VERSION 5.7 ;
  NOWIREEXTENSIONATPIN ON ;
  DIVIDERCHAR "/" ;
  BUSBITCHARS "[]" ;
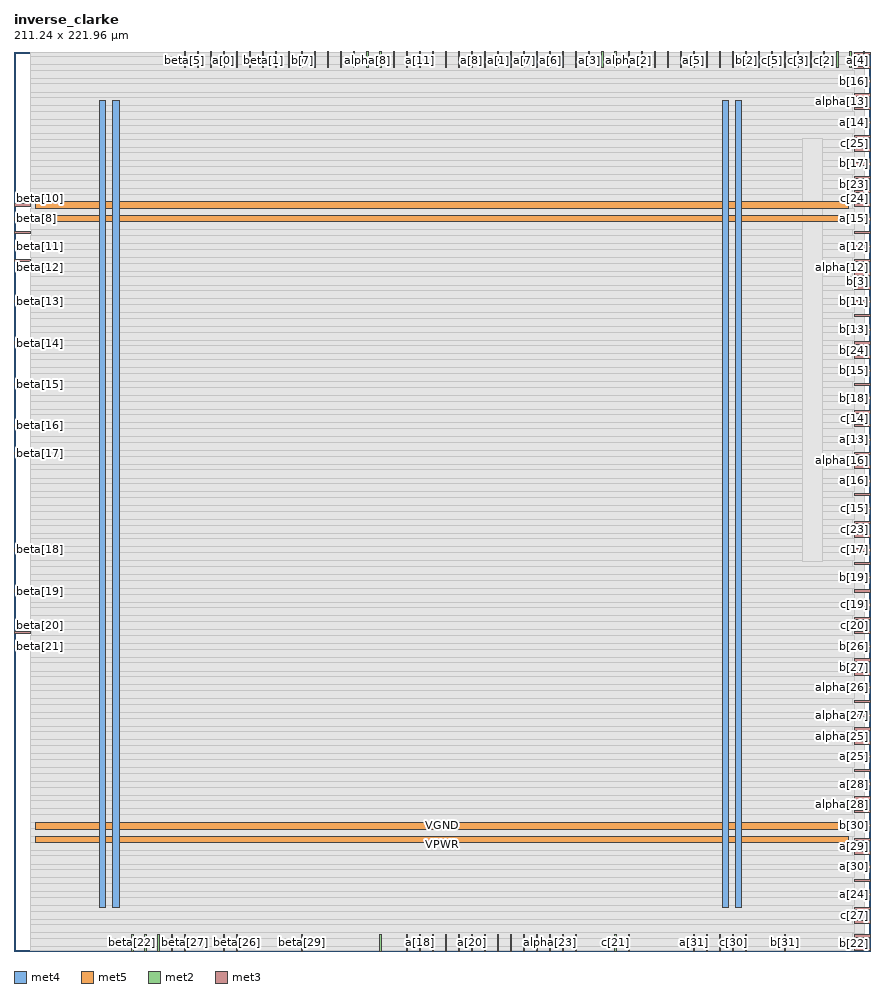
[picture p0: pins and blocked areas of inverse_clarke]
MACRO inverse_clarke
  CLASS BLOCK ;
  FOREIGN inverse_clarke ;
  ORIGIN 0.000 0.000 ;
  SIZE 211.240 BY 221.960 ;
  PIN VGND
    DIRECTION INOUT ;
    USE GROUND ;
    PORT
      LAYER met4 ;
        RECT 24.340 10.640 25.940 209.680 ;
    END
    PORT
      LAYER met4 ;
        RECT 177.940 10.640 179.540 209.680 ;
    END
    PORT
      LAYER met5 ;
        RECT 5.280 30.030 205.860 31.630 ;
    END
    PORT
      LAYER met5 ;
        RECT 5.280 183.210 205.860 184.810 ;
    END
  END VGND
  PIN VPWR
    DIRECTION INOUT ;
    USE POWER ;
    PORT
      LAYER met4 ;
        RECT 21.040 10.640 22.640 209.680 ;
    END
    PORT
      LAYER met4 ;
        RECT 174.640 10.640 176.240 209.680 ;
    END
    PORT
      LAYER met5 ;
        RECT 5.280 26.730 205.860 28.330 ;
    END
    PORT
      LAYER met5 ;
        RECT 5.280 179.910 205.860 181.510 ;
    END
  END VPWR
  PIN a[0]
    DIRECTION OUTPUT ;
    USE SIGNAL ;
    ANTENNADIFFAREA 0.795200 ;
    PORT
      LAYER met2 ;
        RECT 51.610 217.960 51.890 221.960 ;
    END
  END a[0]
  PIN a[10]
    DIRECTION OUTPUT ;
    USE SIGNAL ;
    ANTENNADIFFAREA 0.795200 ;
    PORT
      LAYER met2 ;
        RECT 58.050 217.960 58.330 221.960 ;
    END
  END a[10]
  PIN a[11]
    DIRECTION OUTPUT ;
    USE SIGNAL ;
    ANTENNADIFFAREA 0.795200 ;
    PORT
      LAYER met2 ;
        RECT 99.910 217.960 100.190 221.960 ;
    END
  END a[11]
  PIN a[12]
    DIRECTION OUTPUT ;
    USE SIGNAL ;
    ANTENNADIFFAREA 0.445500 ;
    PORT
      LAYER met3 ;
        RECT 207.240 173.440 211.240 174.040 ;
    END
  END a[12]
  PIN a[13]
    DIRECTION OUTPUT ;
    USE SIGNAL ;
    ANTENNADIFFAREA 0.795200 ;
    PORT
      LAYER met3 ;
        RECT 207.240 125.840 211.240 126.440 ;
    END
  END a[13]
  PIN a[14]
    DIRECTION OUTPUT ;
    USE SIGNAL ;
    ANTENNADIFFAREA 0.795200 ;
    PORT
      LAYER met3 ;
        RECT 207.240 204.040 211.240 204.640 ;
    END
  END a[14]
  PIN a[15]
    DIRECTION OUTPUT ;
    USE SIGNAL ;
    ANTENNADIFFAREA 0.795200 ;
    PORT
      LAYER met3 ;
        RECT 207.240 180.240 211.240 180.840 ;
    END
  END a[15]
  PIN a[16]
    DIRECTION OUTPUT ;
    USE SIGNAL ;
    ANTENNADIFFAREA 0.795200 ;
    PORT
      LAYER met3 ;
        RECT 207.240 115.640 211.240 116.240 ;
    END
  END a[16]
  PIN a[17]
    DIRECTION OUTPUT ;
    USE SIGNAL ;
    ANTENNADIFFAREA 0.795200 ;
    PORT
      LAYER met3 ;
        RECT 207.240 112.240 211.240 112.840 ;
    END
  END a[17]
  PIN a[18]
    DIRECTION OUTPUT ;
    USE SIGNAL ;
    ANTENNADIFFAREA 0.795200 ;
    PORT
      LAYER met2 ;
        RECT 99.910 0.000 100.190 4.000 ;
    END
  END a[18]
  PIN a[19]
    DIRECTION OUTPUT ;
    USE SIGNAL ;
    ANTENNADIFFAREA 0.795200 ;
    PORT
      LAYER met2 ;
        RECT 103.130 0.000 103.410 4.000 ;
    END
  END a[19]
  PIN a[1]
    DIRECTION OUTPUT ;
    USE SIGNAL ;
    ANTENNADIFFAREA 0.795200 ;
    PORT
      LAYER met2 ;
        RECT 119.230 217.960 119.510 221.960 ;
    END
  END a[1]
  PIN a[20]
    DIRECTION OUTPUT ;
    USE SIGNAL ;
    ANTENNADIFFAREA 0.795200 ;
    PORT
      LAYER met2 ;
        RECT 112.790 0.000 113.070 4.000 ;
    END
  END a[20]
  PIN a[21]
    DIRECTION OUTPUT ;
    USE SIGNAL ;
    ANTENNADIFFAREA 0.795200 ;
    PORT
      LAYER met2 ;
        RECT 122.450 0.000 122.730 4.000 ;
    END
  END a[21]
  PIN a[22]
    DIRECTION OUTPUT ;
    USE SIGNAL ;
    ANTENNADIFFAREA 0.795200 ;
    PORT
      LAYER met2 ;
        RECT 125.670 0.000 125.950 4.000 ;
    END
  END a[22]
  PIN a[23]
    DIRECTION OUTPUT ;
    USE SIGNAL ;
    ANTENNADIFFAREA 0.795200 ;
    PORT
      LAYER met2 ;
        RECT 135.330 0.000 135.610 4.000 ;
    END
  END a[23]
  PIN a[24]
    DIRECTION OUTPUT ;
    USE SIGNAL ;
    ANTENNADIFFAREA 0.795200 ;
    PORT
      LAYER met3 ;
        RECT 207.240 13.640 211.240 14.240 ;
    END
  END a[24]
  PIN a[25]
    DIRECTION OUTPUT ;
    USE SIGNAL ;
    ANTENNADIFFAREA 0.445500 ;
    PORT
      LAYER met3 ;
        RECT 207.240 47.640 211.240 48.240 ;
    END
  END a[25]
  PIN a[26]
    DIRECTION OUTPUT ;
    USE SIGNAL ;
    ANTENNADIFFAREA 0.795200 ;
    PORT
      LAYER met3 ;
        RECT 207.240 71.440 211.240 72.040 ;
    END
  END a[26]
  PIN a[27]
    DIRECTION OUTPUT ;
    USE SIGNAL ;
    ANTENNADIFFAREA 0.795200 ;
    PORT
      LAYER met3 ;
        RECT 207.240 6.840 211.240 7.440 ;
    END
  END a[27]
  PIN a[28]
    DIRECTION OUTPUT ;
    USE SIGNAL ;
    ANTENNADIFFAREA 0.795200 ;
    PORT
      LAYER met3 ;
        RECT 207.240 40.840 211.240 41.440 ;
    END
  END a[28]
  PIN a[29]
    DIRECTION OUTPUT ;
    USE SIGNAL ;
    ANTENNADIFFAREA 0.795200 ;
    PORT
      LAYER met3 ;
        RECT 207.240 27.240 211.240 27.840 ;
    END
  END a[29]
  PIN a[2]
    DIRECTION OUTPUT ;
    USE SIGNAL ;
    ANTENNADIFFAREA 0.795200 ;
    PORT
      LAYER met2 ;
        RECT 135.330 217.960 135.610 221.960 ;
    END
  END a[2]
  PIN a[30]
    DIRECTION OUTPUT ;
    USE SIGNAL ;
    ANTENNADIFFAREA 0.795200 ;
    PORT
      LAYER met3 ;
        RECT 207.240 20.440 211.240 21.040 ;
    END
  END a[30]
  PIN a[31]
    DIRECTION OUTPUT ;
    USE SIGNAL ;
    ANTENNADIFFAREA 0.795200 ;
    PORT
      LAYER met2 ;
        RECT 167.530 0.000 167.810 4.000 ;
    END
  END a[31]
  PIN a[3]
    DIRECTION OUTPUT ;
    USE SIGNAL ;
    ANTENNADIFFAREA 0.795200 ;
    PORT
      LAYER met2 ;
        RECT 141.770 217.960 142.050 221.960 ;
    END
  END a[3]
  PIN a[4]
    DIRECTION OUTPUT ;
    USE SIGNAL ;
    ANTENNADIFFAREA 0.795200 ;
    PORT
      LAYER met2 ;
        RECT 209.390 217.960 209.670 221.960 ;
    END
  END a[4]
  PIN a[5]
    DIRECTION OUTPUT ;
    USE SIGNAL ;
    ANTENNADIFFAREA 0.795200 ;
    PORT
      LAYER met2 ;
        RECT 167.530 217.960 167.810 221.960 ;
    END
  END a[5]
  PIN a[6]
    DIRECTION OUTPUT ;
    USE SIGNAL ;
    ANTENNADIFFAREA 0.795200 ;
    PORT
      LAYER met2 ;
        RECT 132.110 217.960 132.390 221.960 ;
    END
  END a[6]
  PIN a[7]
    DIRECTION OUTPUT ;
    USE SIGNAL ;
    ANTENNADIFFAREA 0.795200 ;
    PORT
      LAYER met2 ;
        RECT 125.670 217.960 125.950 221.960 ;
    END
  END a[7]
  PIN a[8]
    DIRECTION OUTPUT ;
    USE SIGNAL ;
    ANTENNADIFFAREA 0.795200 ;
    PORT
      LAYER met2 ;
        RECT 112.790 217.960 113.070 221.960 ;
    END
  END a[8]
  PIN a[9]
    DIRECTION OUTPUT ;
    USE SIGNAL ;
    ANTENNADIFFAREA 0.795200 ;
    PORT
      LAYER met2 ;
        RECT 103.130 217.960 103.410 221.960 ;
    END
  END a[9]
  PIN alpha[0]
    DIRECTION INPUT ;
    USE SIGNAL ;
    ANTENNAGATEAREA 0.495000 ;
    PORT
      LAYER met2 ;
        RECT 144.990 217.960 145.270 221.960 ;
    END
  END alpha[0]
  PIN alpha[10]
    DIRECTION INPUT ;
    USE SIGNAL ;
    ANTENNAGATEAREA 0.213000 ;
    PORT
      LAYER met2 ;
        RECT 96.690 217.960 96.970 221.960 ;
    END
  END alpha[10]
  PIN alpha[11]
    DIRECTION INPUT ;
    USE SIGNAL ;
    ANTENNAGATEAREA 0.196500 ;
    PORT
      LAYER met2 ;
        RECT 106.350 217.960 106.630 221.960 ;
    END
  END alpha[11]
  PIN alpha[12]
    DIRECTION INPUT ;
    USE SIGNAL ;
    ANTENNAGATEAREA 0.196500 ;
    PORT
      LAYER met3 ;
        RECT 207.240 170.040 211.240 170.640 ;
    END
  END alpha[12]
  PIN alpha[13]
    DIRECTION INPUT ;
    USE SIGNAL ;
    ANTENNAGATEAREA 0.213000 ;
    PORT
      LAYER met3 ;
        RECT 207.240 207.440 211.240 208.040 ;
    END
  END alpha[13]
  PIN alpha[14]
    DIRECTION INPUT ;
    USE SIGNAL ;
    ANTENNAGATEAREA 0.196500 ;
    PORT
      LAYER met3 ;
        RECT 207.240 132.640 211.240 133.240 ;
    END
  END alpha[14]
  PIN alpha[15]
    DIRECTION INPUT ;
    USE SIGNAL ;
    ANTENNAGATEAREA 0.196500 ;
    PORT
      LAYER met3 ;
        RECT 207.240 200.640 211.240 201.240 ;
    END
  END alpha[15]
  PIN alpha[16]
    DIRECTION INPUT ;
    USE SIGNAL ;
    ANTENNAGATEAREA 0.126000 ;
    PORT
      LAYER met3 ;
        RECT 207.240 119.040 211.240 119.640 ;
    END
  END alpha[16]
  PIN alpha[17]
    DIRECTION INPUT ;
    USE SIGNAL ;
    ANTENNAGATEAREA 0.196500 ;
    PORT
      LAYER met3 ;
        RECT 207.240 122.440 211.240 123.040 ;
    END
  END alpha[17]
  PIN alpha[18]
    DIRECTION INPUT ;
    USE SIGNAL ;
    ANTENNAGATEAREA 0.126000 ;
    PORT
      LAYER met2 ;
        RECT 106.350 0.000 106.630 4.000 ;
    END
  END alpha[18]
  PIN alpha[19]
    DIRECTION INPUT ;
    USE SIGNAL ;
    ANTENNAGATEAREA 0.159000 ;
    PORT
      LAYER met2 ;
        RECT 109.570 0.000 109.850 4.000 ;
    END
  END alpha[19]
  PIN alpha[1]
    DIRECTION INPUT ;
    USE SIGNAL ;
    ANTENNAGATEAREA 0.742500 ;
    PORT
      LAYER met2 ;
        RECT 138.550 217.960 138.830 221.960 ;
    END
  END alpha[1]
  PIN alpha[20]
    DIRECTION INPUT ;
    USE SIGNAL ;
    ANTENNAGATEAREA 0.196500 ;
    PORT
      LAYER met2 ;
        RECT 116.010 0.000 116.290 4.000 ;
    END
  END alpha[20]
  PIN alpha[21]
    DIRECTION INPUT ;
    USE SIGNAL ;
    ANTENNAGATEAREA 0.196500 ;
    PORT
      LAYER met2 ;
        RECT 119.230 0.000 119.510 4.000 ;
    END
  END alpha[21]
  PIN alpha[22]
    DIRECTION INPUT ;
    USE SIGNAL ;
    ANTENNAGATEAREA 0.213000 ;
    PORT
      LAYER met2 ;
        RECT 128.890 0.000 129.170 4.000 ;
    END
  END alpha[22]
  PIN alpha[23]
    DIRECTION INPUT ;
    USE SIGNAL ;
    ANTENNAGATEAREA 0.196500 ;
    PORT
      LAYER met2 ;
        RECT 132.110 0.000 132.390 4.000 ;
    END
  END alpha[23]
  PIN alpha[24]
    DIRECTION INPUT ;
    USE SIGNAL ;
    ANTENNAGATEAREA 0.213000 ;
    PORT
      LAYER met3 ;
        RECT 207.240 17.040 211.240 17.640 ;
    END
  END alpha[24]
  PIN alpha[25]
    DIRECTION INPUT ;
    USE SIGNAL ;
    ANTENNAGATEAREA 0.196500 ;
    PORT
      LAYER met3 ;
        RECT 207.240 51.040 211.240 51.640 ;
    END
  END alpha[25]
  PIN alpha[26]
    DIRECTION INPUT ;
    USE SIGNAL ;
    ANTENNAGATEAREA 0.213000 ;
    PORT
      LAYER met3 ;
        RECT 207.240 64.640 211.240 65.240 ;
    END
  END alpha[26]
  PIN alpha[27]
    DIRECTION INPUT ;
    USE SIGNAL ;
    ANTENNAGATEAREA 0.196500 ;
    PORT
      LAYER met3 ;
        RECT 207.240 57.840 211.240 58.440 ;
    END
  END alpha[27]
  PIN alpha[28]
    DIRECTION INPUT ;
    USE SIGNAL ;
    ANTENNAGATEAREA 0.213000 ;
    PORT
      LAYER met3 ;
        RECT 207.240 37.440 211.240 38.040 ;
    END
  END alpha[28]
  PIN alpha[29]
    DIRECTION INPUT ;
    USE SIGNAL ;
    ANTENNAGATEAREA 0.196500 ;
    PORT
      LAYER met3 ;
        RECT 207.240 44.240 211.240 44.840 ;
    END
  END alpha[29]
  PIN alpha[2]
    DIRECTION INPUT ;
    USE SIGNAL ;
    ANTENNAGATEAREA 0.196500 ;
    PORT
      LAYER met2 ;
        RECT 151.430 217.960 151.710 221.960 ;
    END
  END alpha[2]
  PIN alpha[30]
    DIRECTION INPUT ;
    USE SIGNAL ;
    ANTENNAGATEAREA 0.196500 ;
    PORT
      LAYER met3 ;
        RECT 207.240 23.840 211.240 24.440 ;
    END
  END alpha[30]
  PIN alpha[31]
    DIRECTION INPUT ;
    USE SIGNAL ;
    ANTENNAGATEAREA 0.213000 ;
    PORT
      LAYER met2 ;
        RECT 170.750 0.000 171.030 4.000 ;
    END
  END alpha[31]
  PIN alpha[3]
    DIRECTION INPUT ;
    USE SIGNAL ;
    ANTENNAGATEAREA 0.196500 ;
    PORT
      LAYER met2 ;
        RECT 173.970 217.960 174.250 221.960 ;
    END
  END alpha[3]
  PIN alpha[4]
    DIRECTION INPUT ;
    USE SIGNAL ;
    ANTENNAGATEAREA 0.213000 ;
    PORT
      LAYER met2 ;
        RECT 157.870 217.960 158.150 221.960 ;
    END
  END alpha[4]
  PIN alpha[5]
    DIRECTION INPUT ;
    USE SIGNAL ;
    ANTENNAGATEAREA 0.196500 ;
    PORT
      LAYER met2 ;
        RECT 161.090 217.960 161.370 221.960 ;
    END
  END alpha[5]
  PIN alpha[6]
    DIRECTION INPUT ;
    USE SIGNAL ;
    ANTENNAGATEAREA 0.126000 ;
    PORT
      LAYER met2 ;
        RECT 74.150 217.960 74.430 221.960 ;
    END
  END alpha[6]
  PIN alpha[7]
    DIRECTION INPUT ;
    USE SIGNAL ;
    ANTENNAGATEAREA 0.213000 ;
    PORT
      LAYER met2 ;
        RECT 77.370 217.960 77.650 221.960 ;
    END
  END alpha[7]
  PIN alpha[8]
    DIRECTION INPUT ;
    USE SIGNAL ;
    ANTENNAGATEAREA 0.196500 ;
    PORT
      LAYER met2 ;
        RECT 87.030 217.960 87.310 221.960 ;
    END
  END alpha[8]
  PIN alpha[9]
    DIRECTION INPUT ;
    USE SIGNAL ;
    ANTENNAGATEAREA 0.196500 ;
    PORT
      LAYER met2 ;
        RECT 83.810 217.960 84.090 221.960 ;
    END
  END alpha[9]
  PIN b[0]
    DIRECTION OUTPUT ;
    USE SIGNAL ;
    ANTENNADIFFAREA 0.795200 ;
    PORT
      LAYER met2 ;
        RECT 154.650 217.960 154.930 221.960 ;
    END
  END b[0]
  PIN b[10]
    DIRECTION OUTPUT ;
    USE SIGNAL ;
    ANTENNADIFFAREA 0.795200 ;
    PORT
      LAYER met2 ;
        RECT 109.570 217.960 109.850 221.960 ;
    END
  END b[10]
  PIN b[11]
    DIRECTION OUTPUT ;
    USE SIGNAL ;
    ANTENNADIFFAREA 0.445500 ;
    PORT
      LAYER met3 ;
        RECT 207.240 159.840 211.240 160.440 ;
    END
  END b[11]
  PIN b[12]
    DIRECTION OUTPUT ;
    USE SIGNAL ;
    ANTENNADIFFAREA 0.445500 ;
    PORT
      LAYER met3 ;
        RECT 207.240 166.640 211.240 167.240 ;
    END
  END b[12]
  PIN b[13]
    DIRECTION OUTPUT ;
    USE SIGNAL ;
    ANTENNADIFFAREA 0.795200 ;
    PORT
      LAYER met3 ;
        RECT 207.240 153.040 211.240 153.640 ;
    END
  END b[13]
  PIN b[14]
    DIRECTION OUTPUT ;
    USE SIGNAL ;
    ANTENNADIFFAREA 0.795200 ;
    PORT
      LAYER met3 ;
        RECT 207.240 210.840 211.240 211.440 ;
    END
  END b[14]
  PIN b[15]
    DIRECTION OUTPUT ;
    USE SIGNAL ;
    ANTENNADIFFAREA 0.795200 ;
    PORT
      LAYER met3 ;
        RECT 207.240 142.840 211.240 143.440 ;
    END
  END b[15]
  PIN b[16]
    DIRECTION OUTPUT ;
    USE SIGNAL ;
    ANTENNADIFFAREA 0.795200 ;
    PORT
      LAYER met3 ;
        RECT 207.240 214.240 211.240 214.840 ;
    END
  END b[16]
  PIN b[17]
    DIRECTION OUTPUT ;
    USE SIGNAL ;
    ANTENNADIFFAREA 0.795200 ;
    PORT
      LAYER met3 ;
        RECT 207.240 193.840 211.240 194.440 ;
    END
  END b[17]
  PIN b[18]
    DIRECTION OUTPUT ;
    USE SIGNAL ;
    ANTENNADIFFAREA 0.445500 ;
    PORT
      LAYER met3 ;
        RECT 207.240 136.040 211.240 136.640 ;
    END
  END b[18]
  PIN b[19]
    DIRECTION OUTPUT ;
    USE SIGNAL ;
    ANTENNADIFFAREA 0.445500 ;
    PORT
      LAYER met3 ;
        RECT 207.240 91.840 211.240 92.440 ;
    END
  END b[19]
  PIN b[1]
    DIRECTION OUTPUT ;
    USE SIGNAL ;
    ANTENNADIFFAREA 0.795200 ;
    PORT
      LAYER met2 ;
        RECT 170.750 217.960 171.030 221.960 ;
    END
  END b[1]
  PIN b[20]
    DIRECTION OUTPUT ;
    USE SIGNAL ;
    ANTENNADIFFAREA 0.795200 ;
    PORT
      LAYER met3 ;
        RECT 207.240 78.240 211.240 78.840 ;
    END
  END b[20]
  PIN b[21]
    DIRECTION OUTPUT ;
    USE SIGNAL ;
    ANTENNADIFFAREA 0.795200 ;
    PORT
      LAYER met3 ;
        RECT 207.240 3.440 211.240 4.040 ;
    END
  END b[21]
  PIN b[22]
    DIRECTION OUTPUT ;
    USE SIGNAL ;
    ANTENNADIFFAREA 0.795200 ;
    PORT
      LAYER met3 ;
        RECT 207.240 0.040 211.240 0.640 ;
    END
  END b[22]
  PIN b[23]
    DIRECTION OUTPUT ;
    USE SIGNAL ;
    ANTENNADIFFAREA 0.795200 ;
    PORT
      LAYER met3 ;
        RECT 207.240 190.440 211.240 191.040 ;
    END
  END b[23]
  PIN b[24]
    DIRECTION OUTPUT ;
    USE SIGNAL ;
    ANTENNADIFFAREA 0.445500 ;
    PORT
      LAYER met3 ;
        RECT 207.240 146.240 211.240 146.840 ;
    END
  END b[24]
  PIN b[25]
    DIRECTION OUTPUT ;
    USE SIGNAL ;
    ANTENNADIFFAREA 0.795200 ;
    PORT
      LAYER met3 ;
        RECT 207.240 95.240 211.240 95.840 ;
    END
  END b[25]
  PIN b[26]
    DIRECTION OUTPUT ;
    USE SIGNAL ;
    ANTENNADIFFAREA 0.445500 ;
    PORT
      LAYER met3 ;
        RECT 207.240 74.840 211.240 75.440 ;
    END
  END b[26]
  PIN b[27]
    DIRECTION OUTPUT ;
    USE SIGNAL ;
    ANTENNADIFFAREA 0.795200 ;
    PORT
      LAYER met3 ;
        RECT 207.240 68.040 211.240 68.640 ;
    END
  END b[27]
  PIN b[28]
    DIRECTION OUTPUT ;
    USE SIGNAL ;
    ANTENNADIFFAREA 0.795200 ;
    PORT
      LAYER met3 ;
        RECT 207.240 61.240 211.240 61.840 ;
    END
  END b[28]
  PIN b[29]
    DIRECTION OUTPUT ;
    USE SIGNAL ;
    ANTENNADIFFAREA 0.795200 ;
    PORT
      LAYER met3 ;
        RECT 207.240 34.040 211.240 34.640 ;
    END
  END b[29]
  PIN b[2]
    DIRECTION OUTPUT ;
    USE SIGNAL ;
    ANTENNADIFFAREA 0.795200 ;
    PORT
      LAYER met2 ;
        RECT 180.410 217.960 180.690 221.960 ;
    END
  END b[2]
  PIN b[30]
    DIRECTION OUTPUT ;
    USE SIGNAL ;
    ANTENNADIFFAREA 0.445500 ;
    PORT
      LAYER met3 ;
        RECT 207.240 30.640 211.240 31.240 ;
    END
  END b[30]
  PIN b[31]
    DIRECTION OUTPUT ;
    USE SIGNAL ;
    ANTENNADIFFAREA 0.795200 ;
    PORT
      LAYER met2 ;
        RECT 190.070 0.000 190.350 4.000 ;
    END
  END b[31]
  PIN b[3]
    DIRECTION OUTPUT ;
    USE SIGNAL ;
    ANTENNADIFFAREA 0.795200 ;
    PORT
      LAYER met3 ;
        RECT 207.240 163.240 211.240 163.840 ;
    END
  END b[3]
  PIN b[4]
    DIRECTION OUTPUT ;
    USE SIGNAL ;
    ANTENNADIFFAREA 0.445500 ;
    PORT
      LAYER met3 ;
        RECT 207.240 176.840 211.240 177.440 ;
    END
  END b[4]
  PIN b[5]
    DIRECTION OUTPUT ;
    USE SIGNAL ;
    ANTENNADIFFAREA 0.445500 ;
    PORT
      LAYER met3 ;
        RECT 207.240 187.040 211.240 187.640 ;
    END
  END b[5]
  PIN b[6]
    DIRECTION OUTPUT ;
    USE SIGNAL ;
    ANTENNADIFFAREA 0.795200 ;
    PORT
      LAYER met3 ;
        RECT 207.240 149.640 211.240 150.240 ;
    END
  END b[6]
  PIN b[7]
    DIRECTION OUTPUT ;
    USE SIGNAL ;
    ANTENNADIFFAREA 0.795200 ;
    PORT
      LAYER met2 ;
        RECT 70.930 217.960 71.210 221.960 ;
    END
  END b[7]
  PIN b[8]
    DIRECTION OUTPUT ;
    USE SIGNAL ;
    ANTENNADIFFAREA 0.795200 ;
    PORT
      LAYER met2 ;
        RECT 128.890 217.960 129.170 221.960 ;
    END
  END b[8]
  PIN b[9]
    DIRECTION OUTPUT ;
    USE SIGNAL ;
    ANTENNADIFFAREA 0.795200 ;
    PORT
      LAYER met2 ;
        RECT 116.010 217.960 116.290 221.960 ;
    END
  END b[9]
  PIN beta[0]
    DIRECTION INPUT ;
    USE SIGNAL ;
    ANTENNAGATEAREA 0.196500 ;
    PORT
      LAYER met2 ;
        RECT 80.590 217.960 80.870 221.960 ;
    END
  END beta[0]
  PIN beta[10]
    DIRECTION INPUT ;
    USE SIGNAL ;
    ANTENNAGATEAREA 0.196500 ;
    PORT
      LAYER met3 ;
        RECT 0.000 183.640 4.000 184.240 ;
    END
  END beta[10]
  PIN beta[11]
    DIRECTION INPUT ;
    USE SIGNAL ;
    ANTENNAGATEAREA 0.196500 ;
    PORT
      LAYER met3 ;
        RECT 0.000 173.440 4.000 174.040 ;
    END
  END beta[11]
  PIN beta[12]
    DIRECTION INPUT ;
    USE SIGNAL ;
    ANTENNAGATEAREA 0.196500 ;
    PORT
      LAYER met3 ;
        RECT 0.000 170.040 4.000 170.640 ;
    END
  END beta[12]
  PIN beta[13]
    DIRECTION INPUT ;
    USE SIGNAL ;
    ANTENNAGATEAREA 0.196500 ;
    PORT
      LAYER met3 ;
        RECT 0.000 159.840 4.000 160.440 ;
    END
  END beta[13]
  PIN beta[14]
    DIRECTION INPUT ;
    USE SIGNAL ;
    ANTENNAGATEAREA 0.196500 ;
    PORT
      LAYER met3 ;
        RECT 0.000 149.640 4.000 150.240 ;
    END
  END beta[14]
  PIN beta[15]
    DIRECTION INPUT ;
    USE SIGNAL ;
    ANTENNAGATEAREA 0.196500 ;
    PORT
      LAYER met3 ;
        RECT 0.000 139.440 4.000 140.040 ;
    END
  END beta[15]
  PIN beta[16]
    DIRECTION INPUT ;
    USE SIGNAL ;
    ANTENNAGATEAREA 0.126000 ;
    PORT
      LAYER met3 ;
        RECT 0.000 129.240 4.000 129.840 ;
    END
  END beta[16]
  PIN beta[17]
    DIRECTION INPUT ;
    USE SIGNAL ;
    ANTENNAGATEAREA 0.196500 ;
    PORT
      LAYER met3 ;
        RECT 0.000 122.440 4.000 123.040 ;
    END
  END beta[17]
  PIN beta[18]
    DIRECTION INPUT ;
    USE SIGNAL ;
    ANTENNAGATEAREA 0.196500 ;
    PORT
      LAYER met3 ;
        RECT 0.000 98.640 4.000 99.240 ;
    END
  END beta[18]
  PIN beta[19]
    DIRECTION INPUT ;
    USE SIGNAL ;
    ANTENNAGATEAREA 0.196500 ;
    PORT
      LAYER met3 ;
        RECT 0.000 88.440 4.000 89.040 ;
    END
  END beta[19]
  PIN beta[1]
    DIRECTION INPUT ;
    USE SIGNAL ;
    ANTENNAGATEAREA 0.196500 ;
    PORT
      LAYER met2 ;
        RECT 61.270 217.960 61.550 221.960 ;
    END
  END beta[1]
  PIN beta[20]
    DIRECTION INPUT ;
    USE SIGNAL ;
    ANTENNAGATEAREA 0.196500 ;
    PORT
      LAYER met3 ;
        RECT 0.000 78.240 4.000 78.840 ;
    END
  END beta[20]
  PIN beta[21]
    DIRECTION INPUT ;
    USE SIGNAL ;
    ANTENNAGATEAREA 0.213000 ;
    PORT
      LAYER met3 ;
        RECT 0.000 74.840 4.000 75.440 ;
    END
  END beta[21]
  PIN beta[22]
    DIRECTION INPUT ;
    USE SIGNAL ;
    ANTENNAGATEAREA 0.196500 ;
    PORT
      LAYER met2 ;
        RECT 29.070 0.000 29.350 4.000 ;
    END
  END beta[22]
  PIN beta[23]
    DIRECTION INPUT ;
    USE SIGNAL ;
    ANTENNAGATEAREA 0.196500 ;
    PORT
      LAYER met2 ;
        RECT 32.290 0.000 32.570 4.000 ;
    END
  END beta[23]
  PIN beta[24]
    DIRECTION INPUT ;
    USE SIGNAL ;
    ANTENNAGATEAREA 0.196500 ;
    PORT
      LAYER met2 ;
        RECT 35.510 0.000 35.790 4.000 ;
    END
  END beta[24]
  PIN beta[25]
    DIRECTION INPUT ;
    USE SIGNAL ;
    ANTENNAGATEAREA 0.196500 ;
    PORT
      LAYER met2 ;
        RECT 51.610 0.000 51.890 4.000 ;
    END
  END beta[25]
  PIN beta[26]
    DIRECTION INPUT ;
    USE SIGNAL ;
    ANTENNAGATEAREA 0.196500 ;
    PORT
      LAYER met2 ;
        RECT 54.830 0.000 55.110 4.000 ;
    END
  END beta[26]
  PIN beta[27]
    DIRECTION INPUT ;
    USE SIGNAL ;
    ANTENNAGATEAREA 0.196500 ;
    PORT
      LAYER met2 ;
        RECT 41.950 0.000 42.230 4.000 ;
    END
  END beta[27]
  PIN beta[28]
    DIRECTION INPUT ;
    USE SIGNAL ;
    ANTENNAGATEAREA 0.126000 ;
    PORT
      LAYER met2 ;
        RECT 38.730 0.000 39.010 4.000 ;
    END
  END beta[28]
  PIN beta[29]
    DIRECTION INPUT ;
    USE SIGNAL ;
    ANTENNAGATEAREA 0.196500 ;
    PORT
      LAYER met2 ;
        RECT 70.930 0.000 71.210 4.000 ;
    END
  END beta[29]
  PIN beta[2]
    DIRECTION INPUT ;
    USE SIGNAL ;
    ANTENNAGATEAREA 0.213000 ;
    PORT
      LAYER met2 ;
        RECT 64.490 217.960 64.770 221.960 ;
    END
  END beta[2]
  PIN beta[30]
    DIRECTION INPUT ;
    USE SIGNAL ;
    ANTENNAGATEAREA 0.213000 ;
    PORT
      LAYER met2 ;
        RECT 90.250 0.000 90.530 4.000 ;
    END
  END beta[30]
  PIN beta[31]
    DIRECTION INPUT ;
    USE SIGNAL ;
    ANTENNAGATEAREA 0.196500 ;
    PORT
      LAYER met2 ;
        RECT 96.690 0.000 96.970 4.000 ;
    END
  END beta[31]
  PIN beta[3]
    DIRECTION INPUT ;
    USE SIGNAL ;
    ANTENNAGATEAREA 0.196500 ;
    PORT
      LAYER met2 ;
        RECT 67.710 217.960 67.990 221.960 ;
    END
  END beta[3]
  PIN beta[4]
    DIRECTION INPUT ;
    USE SIGNAL ;
    ANTENNAGATEAREA 0.196500 ;
    PORT
      LAYER met2 ;
        RECT 54.830 217.960 55.110 221.960 ;
    END
  END beta[4]
  PIN beta[5]
    DIRECTION INPUT ;
    USE SIGNAL ;
    ANTENNAGATEAREA 0.196500 ;
    PORT
      LAYER met2 ;
        RECT 41.950 217.960 42.230 221.960 ;
    END
  END beta[5]
  PIN beta[6]
    DIRECTION INPUT ;
    USE SIGNAL ;
    ANTENNAGATEAREA 0.196500 ;
    PORT
      LAYER met2 ;
        RECT 48.390 217.960 48.670 221.960 ;
    END
  END beta[6]
  PIN beta[7]
    DIRECTION INPUT ;
    USE SIGNAL ;
    ANTENNAGATEAREA 0.196500 ;
    PORT
      LAYER met2 ;
        RECT 45.170 217.960 45.450 221.960 ;
    END
  END beta[7]
  PIN beta[8]
    DIRECTION INPUT ;
    USE SIGNAL ;
    ANTENNAGATEAREA 0.196500 ;
    PORT
      LAYER met3 ;
        RECT 0.000 180.240 4.000 180.840 ;
    END
  END beta[8]
  PIN beta[9]
    DIRECTION INPUT ;
    USE SIGNAL ;
    ANTENNAGATEAREA 0.196500 ;
    PORT
      LAYER met3 ;
        RECT 0.000 176.840 4.000 177.440 ;
    END
  END beta[9]
  PIN c[0]
    DIRECTION OUTPUT ;
    USE SIGNAL ;
    ANTENNADIFFAREA 0.795200 ;
    PORT
      LAYER met2 ;
        RECT 164.310 217.960 164.590 221.960 ;
    END
  END c[0]
  PIN c[10]
    DIRECTION OUTPUT ;
    USE SIGNAL ;
    ANTENNADIFFAREA 0.795200 ;
    PORT
      LAYER met2 ;
        RECT 90.250 217.960 90.530 221.960 ;
    END
  END c[10]
  PIN c[11]
    DIRECTION OUTPUT ;
    USE SIGNAL ;
    ANTENNADIFFAREA 0.445500 ;
    PORT
      LAYER met3 ;
        RECT 207.240 139.440 211.240 140.040 ;
    END
  END c[11]
  PIN c[12]
    DIRECTION OUTPUT ;
    USE SIGNAL ;
    ANTENNADIFFAREA 0.795200 ;
    PORT
      LAYER met3 ;
        RECT 207.240 156.440 211.240 157.040 ;
    END
  END c[12]
  PIN c[13]
    DIRECTION OUTPUT ;
    USE SIGNAL ;
    ANTENNADIFFAREA 0.795200 ;
    PORT
      LAYER met3 ;
        RECT 207.240 221.040 211.240 221.640 ;
    END
  END c[13]
  PIN c[14]
    DIRECTION OUTPUT ;
    USE SIGNAL ;
    ANTENNADIFFAREA 0.795200 ;
    PORT
      LAYER met3 ;
        RECT 207.240 129.240 211.240 129.840 ;
    END
  END c[14]
  PIN c[15]
    DIRECTION OUTPUT ;
    USE SIGNAL ;
    ANTENNADIFFAREA 0.795200 ;
    PORT
      LAYER met3 ;
        RECT 207.240 108.840 211.240 109.440 ;
    END
  END c[15]
  PIN c[16]
    DIRECTION OUTPUT ;
    USE SIGNAL ;
    ANTENNADIFFAREA 0.795200 ;
    PORT
      LAYER met3 ;
        RECT 207.240 217.640 211.240 218.240 ;
    END
  END c[16]
  PIN c[17]
    DIRECTION OUTPUT ;
    USE SIGNAL ;
    ANTENNADIFFAREA 0.795200 ;
    PORT
      LAYER met3 ;
        RECT 207.240 98.640 211.240 99.240 ;
    END
  END c[17]
  PIN c[18]
    DIRECTION OUTPUT ;
    USE SIGNAL ;
    ANTENNADIFFAREA 0.795200 ;
    PORT
      LAYER met3 ;
        RECT 207.240 105.440 211.240 106.040 ;
    END
  END c[18]
  PIN c[19]
    DIRECTION OUTPUT ;
    USE SIGNAL ;
    ANTENNADIFFAREA 0.795200 ;
    PORT
      LAYER met3 ;
        RECT 207.240 85.040 211.240 85.640 ;
    END
  END c[19]
  PIN c[1]
    DIRECTION OUTPUT ;
    USE SIGNAL ;
    ANTENNADIFFAREA 0.795200 ;
    PORT
      LAYER met2 ;
        RECT 177.190 217.960 177.470 221.960 ;
    END
  END c[1]
  PIN c[20]
    DIRECTION OUTPUT ;
    USE SIGNAL ;
    ANTENNADIFFAREA 0.445500 ;
    PORT
      LAYER met3 ;
        RECT 207.240 81.640 211.240 82.240 ;
    END
  END c[20]
  PIN c[21]
    DIRECTION OUTPUT ;
    USE SIGNAL ;
    ANTENNADIFFAREA 0.795200 ;
    PORT
      LAYER met2 ;
        RECT 148.210 0.000 148.490 4.000 ;
    END
  END c[21]
  PIN c[22]
    DIRECTION OUTPUT ;
    USE SIGNAL ;
    ANTENNADIFFAREA 0.795200 ;
    PORT
      LAYER met2 ;
        RECT 151.430 0.000 151.710 4.000 ;
    END
  END c[22]
  PIN c[23]
    DIRECTION OUTPUT ;
    USE SIGNAL ;
    ANTENNADIFFAREA 0.795200 ;
    PORT
      LAYER met3 ;
        RECT 207.240 102.040 211.240 102.640 ;
    END
  END c[23]
  PIN c[24]
    DIRECTION OUTPUT ;
    USE SIGNAL ;
    ANTENNADIFFAREA 0.795200 ;
    PORT
      LAYER met3 ;
        RECT 207.240 183.640 211.240 184.240 ;
    END
  END c[24]
  PIN c[25]
    DIRECTION OUTPUT ;
    USE SIGNAL ;
    ANTENNADIFFAREA 0.795200 ;
    PORT
      LAYER met3 ;
        RECT 207.240 197.240 211.240 197.840 ;
    END
  END c[25]
  PIN c[26]
    DIRECTION OUTPUT ;
    USE SIGNAL ;
    ANTENNADIFFAREA 0.795200 ;
    PORT
      LAYER met3 ;
        RECT 207.240 88.440 211.240 89.040 ;
    END
  END c[26]
  PIN c[27]
    DIRECTION OUTPUT ;
    USE SIGNAL ;
    ANTENNADIFFAREA 0.795200 ;
    PORT
      LAYER met3 ;
        RECT 207.240 10.240 211.240 10.840 ;
    END
  END c[27]
  PIN c[28]
    DIRECTION OUTPUT ;
    USE SIGNAL ;
    ANTENNADIFFAREA 0.795200 ;
    PORT
      LAYER met3 ;
        RECT 207.240 54.440 211.240 55.040 ;
    END
  END c[28]
  PIN c[29]
    DIRECTION OUTPUT ;
    USE SIGNAL ;
    ANTENNADIFFAREA 0.795200 ;
    PORT
      LAYER met2 ;
        RECT 173.970 0.000 174.250 4.000 ;
    END
  END c[29]
  PIN c[2]
    DIRECTION OUTPUT ;
    USE SIGNAL ;
    ANTENNADIFFAREA 0.795200 ;
    PORT
      LAYER met2 ;
        RECT 199.730 217.960 200.010 221.960 ;
    END
  END c[2]
  PIN c[30]
    DIRECTION OUTPUT ;
    USE SIGNAL ;
    ANTENNADIFFAREA 0.795200 ;
    PORT
      LAYER met2 ;
        RECT 177.190 0.000 177.470 4.000 ;
    END
  END c[30]
  PIN c[31]
    DIRECTION OUTPUT ;
    USE SIGNAL ;
    ANTENNADIFFAREA 0.795200 ;
    PORT
      LAYER met2 ;
        RECT 180.410 0.000 180.690 4.000 ;
    END
  END c[31]
  PIN c[3]
    DIRECTION OUTPUT ;
    USE SIGNAL ;
    ANTENNADIFFAREA 0.795200 ;
    PORT
      LAYER met2 ;
        RECT 193.290 217.960 193.570 221.960 ;
    END
  END c[3]
  PIN c[4]
    DIRECTION OUTPUT ;
    USE SIGNAL ;
    ANTENNADIFFAREA 0.795200 ;
    PORT
      LAYER met2 ;
        RECT 190.070 217.960 190.350 221.960 ;
    END
  END c[4]
  PIN c[5]
    DIRECTION OUTPUT ;
    USE SIGNAL ;
    ANTENNADIFFAREA 0.795200 ;
    PORT
      LAYER met2 ;
        RECT 186.850 217.960 187.130 221.960 ;
    END
  END c[5]
  PIN c[6]
    DIRECTION OUTPUT ;
    USE SIGNAL ;
    ANTENNADIFFAREA 0.795200 ;
    PORT
      LAYER met2 ;
        RECT 183.630 217.960 183.910 221.960 ;
    END
  END c[6]
  PIN c[7]
    DIRECTION OUTPUT ;
    USE SIGNAL ;
    ANTENNADIFFAREA 0.795200 ;
    PORT
      LAYER met2 ;
        RECT 148.210 217.960 148.490 221.960 ;
    END
  END c[7]
  PIN c[8]
    DIRECTION OUTPUT ;
    USE SIGNAL ;
    ANTENNADIFFAREA 0.795200 ;
    PORT
      LAYER met2 ;
        RECT 122.450 217.960 122.730 221.960 ;
    END
  END c[8]
  PIN c[9]
    DIRECTION OUTPUT ;
    USE SIGNAL ;
    ANTENNADIFFAREA 0.795200 ;
    PORT
      LAYER met2 ;
        RECT 93.470 217.960 93.750 221.960 ;
    END
  END c[9]
  PIN clk
    DIRECTION INPUT ;
    USE SIGNAL ;
    ANTENNAGATEAREA 0.852000 ;
    PORT
      LAYER met2 ;
        RECT 138.550 0.000 138.830 4.000 ;
    END
  END clk
  PIN done
    DIRECTION OUTPUT ;
    USE SIGNAL ;
    ANTENNADIFFAREA 0.795200 ;
    PORT
      LAYER met2 ;
        RECT 196.510 217.960 196.790 221.960 ;
    END
  END done
  PIN rstb
    DIRECTION INPUT ;
    USE SIGNAL ;
    ANTENNAGATEAREA 0.196500 ;
    PORT
      LAYER met2 ;
        RECT 206.170 217.960 206.450 221.960 ;
    END
  END rstb
  PIN start
    DIRECTION INPUT ;
    USE SIGNAL ;
    ANTENNAGATEAREA 0.213000 ;
    PORT
      LAYER met2 ;
        RECT 202.950 217.960 203.230 221.960 ;
    END
  END start
  OBS
      LAYER li1 ;
        RECT 5.520 10.795 205.620 209.525 ;
      LAYER met1 ;
        RECT 4.670 10.640 209.690 213.480 ;
      LAYER met2 ;
        RECT 4.690 217.680 41.670 221.525 ;
        RECT 42.510 217.680 44.890 221.525 ;
        RECT 45.730 217.680 48.110 221.525 ;
        RECT 48.950 217.680 51.330 221.525 ;
        RECT 52.170 217.680 54.550 221.525 ;
        RECT 55.390 217.680 57.770 221.525 ;
        RECT 58.610 217.680 60.990 221.525 ;
        RECT 61.830 217.680 64.210 221.525 ;
        RECT 65.050 217.680 67.430 221.525 ;
        RECT 68.270 217.680 70.650 221.525 ;
        RECT 71.490 217.680 73.870 221.525 ;
        RECT 74.710 217.680 77.090 221.525 ;
        RECT 77.930 217.680 80.310 221.525 ;
        RECT 81.150 217.680 83.530 221.525 ;
        RECT 84.370 217.680 86.750 221.525 ;
        RECT 87.590 217.680 89.970 221.525 ;
        RECT 90.810 217.680 93.190 221.525 ;
        RECT 94.030 217.680 96.410 221.525 ;
        RECT 97.250 217.680 99.630 221.525 ;
        RECT 100.470 217.680 102.850 221.525 ;
        RECT 103.690 217.680 106.070 221.525 ;
        RECT 106.910 217.680 109.290 221.525 ;
        RECT 110.130 217.680 112.510 221.525 ;
        RECT 113.350 217.680 115.730 221.525 ;
        RECT 116.570 217.680 118.950 221.525 ;
        RECT 119.790 217.680 122.170 221.525 ;
        RECT 123.010 217.680 125.390 221.525 ;
        RECT 126.230 217.680 128.610 221.525 ;
        RECT 129.450 217.680 131.830 221.525 ;
        RECT 132.670 217.680 135.050 221.525 ;
        RECT 135.890 217.680 138.270 221.525 ;
        RECT 139.110 217.680 141.490 221.525 ;
        RECT 142.330 217.680 144.710 221.525 ;
        RECT 145.550 217.680 147.930 221.525 ;
        RECT 148.770 217.680 151.150 221.525 ;
        RECT 151.990 217.680 154.370 221.525 ;
        RECT 155.210 217.680 157.590 221.525 ;
        RECT 158.430 217.680 160.810 221.525 ;
        RECT 161.650 217.680 164.030 221.525 ;
        RECT 164.870 217.680 167.250 221.525 ;
        RECT 168.090 217.680 170.470 221.525 ;
        RECT 171.310 217.680 173.690 221.525 ;
        RECT 174.530 217.680 176.910 221.525 ;
        RECT 177.750 217.680 180.130 221.525 ;
        RECT 180.970 217.680 183.350 221.525 ;
        RECT 184.190 217.680 186.570 221.525 ;
        RECT 187.410 217.680 189.790 221.525 ;
        RECT 190.630 217.680 193.010 221.525 ;
        RECT 193.850 217.680 196.230 221.525 ;
        RECT 197.070 217.680 199.450 221.525 ;
        RECT 200.290 217.680 202.670 221.525 ;
        RECT 203.510 217.680 205.890 221.525 ;
        RECT 206.730 217.680 209.110 221.525 ;
        RECT 4.690 4.280 209.660 217.680 ;
        RECT 4.690 0.155 28.790 4.280 ;
        RECT 29.630 0.155 32.010 4.280 ;
        RECT 32.850 0.155 35.230 4.280 ;
        RECT 36.070 0.155 38.450 4.280 ;
        RECT 39.290 0.155 41.670 4.280 ;
        RECT 42.510 0.155 51.330 4.280 ;
        RECT 52.170 0.155 54.550 4.280 ;
        RECT 55.390 0.155 70.650 4.280 ;
        RECT 71.490 0.155 89.970 4.280 ;
        RECT 90.810 0.155 96.410 4.280 ;
        RECT 97.250 0.155 99.630 4.280 ;
        RECT 100.470 0.155 102.850 4.280 ;
        RECT 103.690 0.155 106.070 4.280 ;
        RECT 106.910 0.155 109.290 4.280 ;
        RECT 110.130 0.155 112.510 4.280 ;
        RECT 113.350 0.155 115.730 4.280 ;
        RECT 116.570 0.155 118.950 4.280 ;
        RECT 119.790 0.155 122.170 4.280 ;
        RECT 123.010 0.155 125.390 4.280 ;
        RECT 126.230 0.155 128.610 4.280 ;
        RECT 129.450 0.155 131.830 4.280 ;
        RECT 132.670 0.155 135.050 4.280 ;
        RECT 135.890 0.155 138.270 4.280 ;
        RECT 139.110 0.155 147.930 4.280 ;
        RECT 148.770 0.155 151.150 4.280 ;
        RECT 151.990 0.155 167.250 4.280 ;
        RECT 168.090 0.155 170.470 4.280 ;
        RECT 171.310 0.155 173.690 4.280 ;
        RECT 174.530 0.155 176.910 4.280 ;
        RECT 177.750 0.155 180.130 4.280 ;
        RECT 180.970 0.155 189.790 4.280 ;
        RECT 190.630 0.155 209.660 4.280 ;
      LAYER met3 ;
        RECT 3.990 220.640 206.840 221.505 ;
        RECT 3.990 218.640 207.240 220.640 ;
        RECT 3.990 217.240 206.840 218.640 ;
        RECT 3.990 215.240 207.240 217.240 ;
        RECT 3.990 213.840 206.840 215.240 ;
        RECT 3.990 211.840 207.240 213.840 ;
        RECT 3.990 210.440 206.840 211.840 ;
        RECT 3.990 208.440 207.240 210.440 ;
        RECT 3.990 207.040 206.840 208.440 ;
        RECT 3.990 205.040 207.240 207.040 ;
        RECT 3.990 203.640 206.840 205.040 ;
        RECT 3.990 201.640 207.240 203.640 ;
        RECT 3.990 200.240 206.840 201.640 ;
        RECT 3.990 198.240 207.240 200.240 ;
        RECT 3.990 196.840 206.840 198.240 ;
        RECT 3.990 194.840 207.240 196.840 ;
        RECT 3.990 193.440 206.840 194.840 ;
        RECT 3.990 191.440 207.240 193.440 ;
        RECT 3.990 190.040 206.840 191.440 ;
        RECT 3.990 188.040 207.240 190.040 ;
        RECT 3.990 186.640 206.840 188.040 ;
        RECT 3.990 184.640 207.240 186.640 ;
        RECT 4.400 183.240 206.840 184.640 ;
        RECT 3.990 181.240 207.240 183.240 ;
        RECT 4.400 179.840 206.840 181.240 ;
        RECT 3.990 177.840 207.240 179.840 ;
        RECT 4.400 176.440 206.840 177.840 ;
        RECT 3.990 174.440 207.240 176.440 ;
        RECT 4.400 173.040 206.840 174.440 ;
        RECT 3.990 171.040 207.240 173.040 ;
        RECT 4.400 169.640 206.840 171.040 ;
        RECT 3.990 167.640 207.240 169.640 ;
        RECT 3.990 166.240 206.840 167.640 ;
        RECT 3.990 164.240 207.240 166.240 ;
        RECT 3.990 162.840 206.840 164.240 ;
        RECT 3.990 160.840 207.240 162.840 ;
        RECT 4.400 159.440 206.840 160.840 ;
        RECT 3.990 157.440 207.240 159.440 ;
        RECT 3.990 156.040 206.840 157.440 ;
        RECT 3.990 154.040 207.240 156.040 ;
        RECT 3.990 152.640 206.840 154.040 ;
        RECT 3.990 150.640 207.240 152.640 ;
        RECT 4.400 149.240 206.840 150.640 ;
        RECT 3.990 147.240 207.240 149.240 ;
        RECT 3.990 145.840 206.840 147.240 ;
        RECT 3.990 143.840 207.240 145.840 ;
        RECT 3.990 142.440 206.840 143.840 ;
        RECT 3.990 140.440 207.240 142.440 ;
        RECT 4.400 139.040 206.840 140.440 ;
        RECT 3.990 137.040 207.240 139.040 ;
        RECT 3.990 135.640 206.840 137.040 ;
        RECT 3.990 133.640 207.240 135.640 ;
        RECT 3.990 132.240 206.840 133.640 ;
        RECT 3.990 130.240 207.240 132.240 ;
        RECT 4.400 128.840 206.840 130.240 ;
        RECT 3.990 126.840 207.240 128.840 ;
        RECT 3.990 125.440 206.840 126.840 ;
        RECT 3.990 123.440 207.240 125.440 ;
        RECT 4.400 122.040 206.840 123.440 ;
        RECT 3.990 120.040 207.240 122.040 ;
        RECT 3.990 118.640 206.840 120.040 ;
        RECT 3.990 116.640 207.240 118.640 ;
        RECT 3.990 115.240 206.840 116.640 ;
        RECT 3.990 113.240 207.240 115.240 ;
        RECT 3.990 111.840 206.840 113.240 ;
        RECT 3.990 109.840 207.240 111.840 ;
        RECT 3.990 108.440 206.840 109.840 ;
        RECT 3.990 106.440 207.240 108.440 ;
        RECT 3.990 105.040 206.840 106.440 ;
        RECT 3.990 103.040 207.240 105.040 ;
        RECT 3.990 101.640 206.840 103.040 ;
        RECT 3.990 99.640 207.240 101.640 ;
        RECT 4.400 98.240 206.840 99.640 ;
        RECT 3.990 96.240 207.240 98.240 ;
        RECT 3.990 94.840 206.840 96.240 ;
        RECT 3.990 92.840 207.240 94.840 ;
        RECT 3.990 91.440 206.840 92.840 ;
        RECT 3.990 89.440 207.240 91.440 ;
        RECT 4.400 88.040 206.840 89.440 ;
        RECT 3.990 86.040 207.240 88.040 ;
        RECT 3.990 84.640 206.840 86.040 ;
        RECT 3.990 82.640 207.240 84.640 ;
        RECT 3.990 81.240 206.840 82.640 ;
        RECT 3.990 79.240 207.240 81.240 ;
        RECT 4.400 77.840 206.840 79.240 ;
        RECT 3.990 75.840 207.240 77.840 ;
        RECT 4.400 74.440 206.840 75.840 ;
        RECT 3.990 72.440 207.240 74.440 ;
        RECT 3.990 71.040 206.840 72.440 ;
        RECT 3.990 69.040 207.240 71.040 ;
        RECT 3.990 67.640 206.840 69.040 ;
        RECT 3.990 65.640 207.240 67.640 ;
        RECT 3.990 64.240 206.840 65.640 ;
        RECT 3.990 62.240 207.240 64.240 ;
        RECT 3.990 60.840 206.840 62.240 ;
        RECT 3.990 58.840 207.240 60.840 ;
        RECT 3.990 57.440 206.840 58.840 ;
        RECT 3.990 55.440 207.240 57.440 ;
        RECT 3.990 54.040 206.840 55.440 ;
        RECT 3.990 52.040 207.240 54.040 ;
        RECT 3.990 50.640 206.840 52.040 ;
        RECT 3.990 48.640 207.240 50.640 ;
        RECT 3.990 47.240 206.840 48.640 ;
        RECT 3.990 45.240 207.240 47.240 ;
        RECT 3.990 43.840 206.840 45.240 ;
        RECT 3.990 41.840 207.240 43.840 ;
        RECT 3.990 40.440 206.840 41.840 ;
        RECT 3.990 38.440 207.240 40.440 ;
        RECT 3.990 37.040 206.840 38.440 ;
        RECT 3.990 35.040 207.240 37.040 ;
        RECT 3.990 33.640 206.840 35.040 ;
        RECT 3.990 31.640 207.240 33.640 ;
        RECT 3.990 30.240 206.840 31.640 ;
        RECT 3.990 28.240 207.240 30.240 ;
        RECT 3.990 26.840 206.840 28.240 ;
        RECT 3.990 24.840 207.240 26.840 ;
        RECT 3.990 23.440 206.840 24.840 ;
        RECT 3.990 21.440 207.240 23.440 ;
        RECT 3.990 20.040 206.840 21.440 ;
        RECT 3.990 18.040 207.240 20.040 ;
        RECT 3.990 16.640 206.840 18.040 ;
        RECT 3.990 14.640 207.240 16.640 ;
        RECT 3.990 13.240 206.840 14.640 ;
        RECT 3.990 11.240 207.240 13.240 ;
        RECT 3.990 9.840 206.840 11.240 ;
        RECT 3.990 7.840 207.240 9.840 ;
        RECT 3.990 6.440 206.840 7.840 ;
        RECT 3.990 4.440 207.240 6.440 ;
        RECT 3.990 3.040 206.840 4.440 ;
        RECT 3.990 1.040 207.240 3.040 ;
        RECT 3.990 0.175 206.840 1.040 ;
      LAYER met4 ;
        RECT 194.415 96.055 199.345 200.425 ;
  END
END inverse_clarke
END LIBRARY

